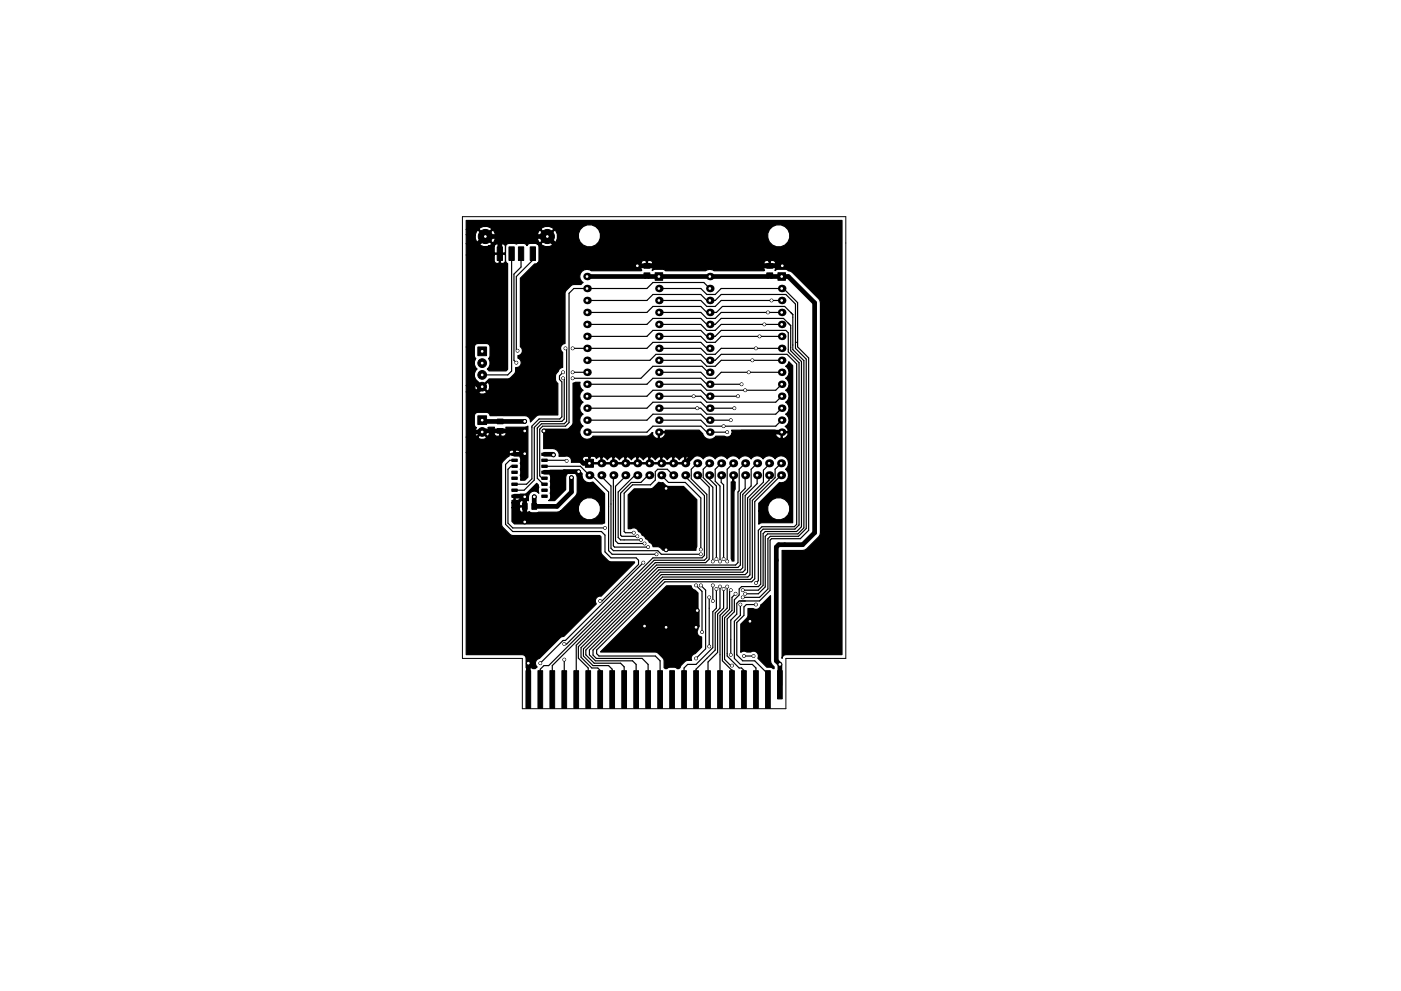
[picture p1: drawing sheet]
<svg xmlns="http://www.w3.org/2000/svg" width="297mm" height="210mm" viewBox="0 0 297 210" stroke-linecap="round" stroke-linejoin="round" font-family="sans-serif">
<path d="M98 46h81.3v93.7h-12.7v10.7h-55.9v-10.7h-12.7z" fill="none" stroke="#000" stroke-width=".21"/>
<g fill="#000" stroke="#000" stroke-width=".21">
<path d="M105.4 52.4h1.1v2.9h-1.1zM107.9 52.4h1.1v2.9h-1.1zM109.9 52.4h1.1v2.9h-1.1zM112.4 52.4h1.1v2.9h-1.1zM136.5 57.9h1.3v1h-1.3zM136.5 55.9h1.3v1h-1.3zM138.9 57.9h1.6v1.6h-1.6zM162.6 57.9h1.2v1h-1.2zM162.6 55.9h1.2v1h-1.2zM164.9 57.9h1.6v1.6h-1.6zM101.3 73.6h1.9v1.9h-1.9zM101.3 88.2h1.9v1.9h-1.9z"/>
<path d="M105.4 88.9h1.3v1h-1.3zM105.4 90.9h1.3v1h-1.3zM108.5 99.9h1.2v.6h-1.2zM108.5 98.7h1.2v.5h-1.2zM108.5 97.4h1.2v.5h-1.2zM108.5 96.1h1.2v.5h-1.2zM114.9 96.1h1.1v.5h-1.1zM114.9 98.7h1.1v.5h-1.1zM114.9 99.9h1.1v.6h-1.1zM114.9 97.4h1.1v.5h-1.1zM124.1 97.4h1.7v1.7h-1.7zM108.5 105h1.2v.5h-1.2z"/>
<path d="M108.5 103.8h1.2v.5h-1.2zM108.5 102.5h1.2v.5h-1.2zM108.5 101.2h1.2v.5h-1.2zM110.8 106.8h1v1.3h-1zM112.8 106.8h1v1.3h-1zM114.9 101.2h1.1v.5h-1.1zM114.9 102.5h1.1v.5h-1.1zM114.9 103.8h1.1v.5h-1.1zM114.9 105h1.1v.5h-1.1zM111.5 142.3h1v8h-1zM114.1 142.3h1v8h-1zM116.6 142.3h1v8h-1z"/>
<path d="M119.1 142.3h1v8h-1zM121.7 142.3h1v8h-1zM124.2 142.3h1v8h-1zM126.8 142.3h1v8h-1zM129.3 142.3h1v8h-1zM131.8 142.3h1v8h-1zM134.4 142.3h1v8h-1zM136.9 142.3h1v8h-1zM139.5 142.3h1v8h-1zM142 142.3h1v8h-1zM144.5 142.3h1v8h-1zM147.1 142.3h1v8h-1z"/>
<path d="M149.6 142.3h1v8h-1zM152.2 142.3h1v8h-1zM154.7 142.3h1v8h-1zM157.2 142.3h1v8h-1zM159.8 142.3h1v8h-1zM162.3 142.3h1v8h-1zM164.9 142.3h1v6h-1z"/>
<circle cx="102.9" cy="50.2" r="1.5"/>
<circle cx="116" cy="50.2" r="1.5"/>
<circle cx="135.1" cy="56.4" r=".4"/>
<circle cx="165.9" cy="56.4" r=".4"/>
<circle cx="102.2" cy="77" r=".92"/>
<circle cx="102.2" cy="79.5" r=".92"/>
<circle cx="109.5" cy="77" r=".3"/>
<circle cx="109.7" cy="74.4" r=".3"/>
<circle cx="119.4" cy="79" r=".3"/>
<circle cx="119.9" cy="73.9" r=".3"/>
<circle cx="121.4" cy="73.9" r=".3"/>
<circle cx="121.4" cy="79" r=".3"/>
<circle cx="158.8" cy="79" r=".3"/>
<circle cx="159.5" cy="76.4" r=".3"/>
<circle cx="160.3" cy="73.9" r=".3"/>
<circle cx="161" cy="71.4" r=".3"/>
<circle cx="162.1" cy="68.8" r=".3"/>
<circle cx="162.8" cy="66.3" r=".3"/>
<circle cx="163.6" cy="63.7" r=".3"/>
<circle cx="102.2" cy="91.6" r=".92"/>
<circle cx="102.2" cy="82" r=".92"/>
<circle cx="111.3" cy="96.3" r=".4"/>
<circle cx="111.3" cy="89.4" r=".4"/>
<circle cx="111.3" cy="91.4" r=".4"/>
<circle cx="115.3" cy="91.4" r=".4"/>
<circle cx="117.3" cy="96.5" r=".4"/>
<circle cx="119.4" cy="80.3" r=".3"/>
<circle cx="120.1" cy="97.8" r=".3"/>
<circle cx="121.4" cy="80.3" r=".3"/>
<circle cx="147.1" cy="84.1" r=".3"/>
<circle cx="147.8" cy="86.6" r=".3"/>
<circle cx="153.4" cy="90.4" r=".3"/>
<circle cx="154.2" cy="91.7" r=".3"/>
<circle cx="154.9" cy="89.1" r=".3"/>
<circle cx="155.7" cy="86.6" r=".3"/>
<circle cx="156.5" cy="84.1" r=".3"/>
<circle cx="157.2" cy="81.5" r=".3"/>
<circle cx="158" cy="82.8" r=".3"/>
<circle cx="111.3" cy="110.7" r=".4"/>
<circle cx="111.3" cy="105.4" r=".4"/>
<circle cx="113.3" cy="105.4" r=".4"/>
<circle cx="121.2" cy="101.3" r=".4"/>
<circle cx="122.7" cy="100.1" r=".4"/>
<circle cx="128.3" cy="112" r=".3"/>
<circle cx="134.4" cy="113" r=".3"/>
<circle cx="135.1" cy="113.8" r=".3"/>
<circle cx="135.9" cy="114.5" r=".3"/>
<circle cx="136.4" cy="119.4" r=".3"/>
<circle cx="136.7" cy="115.3" r=".3"/>
<circle cx="137.4" cy="116.1" r=".3"/>
<circle cx="139.2" cy="117.6" r=".3"/>
<circle cx="141.2" cy="103.6" r=".4"/>
<circle cx="141.2" cy="116.6" r=".4"/>
<circle cx="148.6" cy="116.6" r=".3"/>
<circle cx="148.6" cy="117.6" r=".3"/>
<circle cx="151.1" cy="119.1" r=".3"/>
<circle cx="151.9" cy="118.6" r=".3"/>
<circle cx="152.7" cy="119.1" r=".3"/>
<circle cx="153.4" cy="118.6" r=".3"/>
<circle cx="154.2" cy="119.1" r=".3"/>
<circle cx="119.6" cy="136.6" r=".3"/>
<circle cx="119.6" cy="139.9" r=".3"/>
<circle cx="127.3" cy="127.5" r=".3"/>
<circle cx="136.7" cy="132.8" r=".4"/>
<circle cx="141.2" cy="133.1" r=".4"/>
<circle cx="147.6" cy="133.1" r=".4"/>
<circle cx="147.6" cy="139.7" r=".3"/>
<circle cx="147.6" cy="124.2" r=".3"/>
<circle cx="147.8" cy="129.5" r=".4"/>
<circle cx="148.6" cy="124.2" r=".3"/>
<circle cx="148.8" cy="134.1" r=".3"/>
<circle cx="150.4" cy="137.2" r=".3"/>
<circle cx="150.4" cy="126.7" r=".3"/>
<circle cx="151.1" cy="127.5" r=".3"/>
<circle cx="151.1" cy="124.2" r=".3"/>
<circle cx="151.9" cy="125" r=".3"/>
<circle cx="152.7" cy="124.5" r=".3"/>
<circle cx="153.4" cy="125" r=".3"/>
<circle cx="154.2" cy="124.5" r=".3"/>
<circle cx="154.9" cy="138.9" r=".3"/>
<circle cx="154.9" cy="125.2" r=".3"/>
<circle cx="156" cy="126" r=".3"/>
<circle cx="157" cy="128.3" r=".3"/>
<circle cx="157.5" cy="126.7" r=".3"/>
<circle cx="157.5" cy="125.2" r=".3"/>
<circle cx="157.7" cy="139.2" r=".3"/>
<circle cx="158" cy="126" r=".3"/>
<circle cx="159" cy="131.8" r=".4"/>
<circle cx="159.8" cy="139.2" r=".3"/>
<circle cx="160.3" cy="128.3" r=".3"/>
<circle cx="160.3" cy="123.7" r=".3"/>
<circle cx="112" cy="140.7" r=".4"/>
<circle cx="114.6" cy="140.7" r=".3"/>
<circle cx="155.2" cy="141.2" r=".3"/>
<circle cx="165.4" cy="141" r=".4"/>
</g>
<g fill="#000">
<circle cx="124.5" cy="58.7" r=".8"/>
<circle cx="150.5" cy="58.7" r=".8"/>
<circle cx="124.5" cy="63.7" r=".8"/>
<circle cx="124.5" cy="61.2" r=".8"/>
<circle cx="124.5" cy="76.4" r=".8"/>
<circle cx="124.5" cy="66.3" r=".8"/>
<circle cx="124.5" cy="79" r=".8"/>
<circle cx="124.5" cy="71.4" r=".8"/>
<circle cx="124.5" cy="68.8" r=".8"/>
<circle cx="124.5" cy="73.9" r=".8"/>
<circle cx="139.7" cy="61.2" r=".8"/>
<circle cx="139.7" cy="63.7" r=".8"/>
<circle cx="139.7" cy="68.8" r=".8"/>
<circle cx="139.7" cy="71.4" r=".8"/>
<circle cx="139.7" cy="73.9" r=".8"/>
<circle cx="139.7" cy="76.4" r=".8"/>
<circle cx="139.7" cy="66.3" r=".8"/>
<circle cx="139.7" cy="79" r=".8"/>
<circle cx="150.5" cy="61.2" r=".8"/>
<circle cx="150.5" cy="63.7" r=".8"/>
<circle cx="150.5" cy="79" r=".8"/>
<circle cx="150.5" cy="76.4" r=".8"/>
<circle cx="150.5" cy="68.8" r=".8"/>
<circle cx="150.5" cy="73.9" r=".8"/>
<circle cx="150.5" cy="71.4" r=".8"/>
<circle cx="150.5" cy="66.3" r=".8"/>
<circle cx="165.7" cy="61.2" r=".8"/>
<circle cx="165.7" cy="66.3" r=".8"/>
<circle cx="165.7" cy="71.4" r=".8"/>
<circle cx="165.7" cy="63.7" r=".8"/>
<circle cx="165.7" cy="73.9" r=".8"/>
<circle cx="165.7" cy="76.4" r=".8"/>
<circle cx="165.7" cy="79" r=".8"/>
<circle cx="165.7" cy="68.8" r=".8"/>
<circle cx="124.5" cy="81.5" r=".8"/>
<circle cx="124.5" cy="91.7" r=".8"/>
<circle cx="124.5" cy="89.1" r=".8"/>
<circle cx="124.5" cy="86.6" r=".8"/>
<circle cx="124.5" cy="84.1" r=".8"/>
<circle cx="127.5" cy="98.3" r=".85"/>
<circle cx="130" cy="98.3" r=".85"/>
<circle cx="132.6" cy="98.3" r=".85"/>
<circle cx="135.1" cy="98.3" r=".85"/>
<circle cx="137.7" cy="98.3" r=".85"/>
<circle cx="139.7" cy="84.1" r=".8"/>
<circle cx="139.7" cy="86.6" r=".8"/>
<circle cx="139.7" cy="91.7" r=".8"/>
<circle cx="139.7" cy="89.1" r=".8"/>
<circle cx="139.7" cy="81.5" r=".8"/>
<circle cx="140.2" cy="98.3" r=".85"/>
<circle cx="142.7" cy="98.3" r=".85"/>
<circle cx="145.3" cy="98.3" r=".85"/>
<circle cx="147.8" cy="98.3" r=".85"/>
<circle cx="150.4" cy="98.3" r=".85"/>
<circle cx="150.5" cy="89.1" r=".8"/>
<circle cx="150.5" cy="84.1" r=".8"/>
<circle cx="150.5" cy="81.5" r=".8"/>
<circle cx="150.5" cy="91.7" r=".8"/>
<circle cx="150.5" cy="86.6" r=".8"/>
<circle cx="152.9" cy="98.3" r=".85"/>
<circle cx="155.4" cy="98.3" r=".85"/>
<circle cx="158" cy="98.3" r=".85"/>
<circle cx="160.5" cy="98.3" r=".85"/>
<circle cx="163.1" cy="98.3" r=".85"/>
<circle cx="165.6" cy="98.3" r=".85"/>
<circle cx="165.7" cy="81.5" r=".8"/>
<circle cx="165.7" cy="91.7" r=".8"/>
<circle cx="165.7" cy="84.1" r=".8"/>
<circle cx="165.7" cy="89.1" r=".8"/>
<circle cx="165.7" cy="86.6" r=".8"/>
<circle cx="125" cy="100.8" r=".85"/>
<circle cx="127.5" cy="100.8" r=".85"/>
<circle cx="130" cy="100.8" r=".85"/>
<circle cx="132.6" cy="100.8" r=".85"/>
<circle cx="135.1" cy="100.8" r=".85"/>
<circle cx="137.7" cy="100.8" r=".85"/>
<circle cx="140.2" cy="100.8" r=".85"/>
<circle cx="142.7" cy="100.8" r=".85"/>
<circle cx="145.3" cy="100.8" r=".85"/>
<circle cx="147.8" cy="100.8" r=".85"/>
<circle cx="150.4" cy="100.8" r=".85"/>
<circle cx="152.9" cy="100.8" r=".85"/>
<circle cx="155.4" cy="100.8" r=".85"/>
<circle cx="158" cy="100.8" r=".85"/>
<circle cx="160.5" cy="100.8" r=".85"/>
<circle cx="163.1" cy="100.8" r=".85"/>
<circle cx="165.6" cy="100.8" r=".85"/>
</g>
<g fill="none" stroke="#000" stroke-width="1">
<path d="M105.9 50.2l.1 3.6M105.9 50.2v.3M124.5 58.7h12.4l.3-.3 .2 .3h25.5l.3-.3 .3 .3h3.6l5.6 5.6v48.7l-2.5 2.6h-5.1l-.5 .5v24.1l.8 .8v4.3M135.1 56.4h.1M163.2 56.4h.1M165.9 56.4h-43.7l-6.2-6.2h-13.1l-2.8 2.8v27.5l1.5 1.5h.6l-2.4 2.5v6.4l.7 .7M165.9 56.4h-.1M100.5 91.6l-.9 1v42.8l1.7 1.8h9.2l1.5 1.5v7.6M102.2 89.1l.3 .3h8.7M111.2 91.4h-8.7l-.3 .2h-1.7M111.2 91.4h.1M111.3 89.4h-.1"/>
<path d="M111.3 96.3l-.2 .1h-2M115.3 91.4h6.4l1 1.1v4.8l1 1h1.3M115.4 96.4h1.8l.1 .1M165.7 91.7h-8.5l-4 4.1h-5.4l-2.5 2.5M109.1 105.3h2l.2 .1v5.3M111.3 107.4h.1M111.3 110.7h.1M113.3 105.4h.1M121.2 101.3v3.1l-3.1 3h-4.8v-2M122.7 100.1l-7.3 .1M141.2 103.6v13M136.7 132.8l.2 .3h4.3"/>
<path d="M147.8 129.5v3.3l-.2 .3"/>
</g>
<g fill="none" stroke="#000" stroke-width=".25">
<path d="M108.5 53.8v24.9l-.9 .8h-5.4M110.5 53.8v2.9l-1.5 1.5v18.2l.5 .6M113 53.8v1.4l-3.5 3.5v15.5l.2 .2M137.5 58.7v.2M119.4 79l-.8 .8v.7l.5 .5v7.4l-.4 .5h-4.4l-1.5 1.5v11.2l-1.2 1.1h-2.5M119.9 73.9l.2 .3v15.2l-.5 .5h-4.8l-.9 .9v10.7l1.3 1.2h.2M121.4 79h3.1M121.4 73.9h15.8l1.2-1.3h10.2l1.3 1.3h.6M124.5 71.4h12.7l1.2-1.3h10.2l1.3 1.3h1.7l1.3-1.3h13.7l.5 .5v4.1l2.3 2.3v34.4l-.9 .9h-6.7l-.5 .5v11.1l-.5 .6h-3.6l-.5 .5v1.2l-1 1v2.6l-1.5 1.5v7.9l2.5 2.5h.5l.5 .5v4.1M124.5 66.3h12.7l1.2-1.3h10.2l1.3 1.3h2l1.3-1.3h13.2l1.7 1.7v7.5l2.3 2.3v35.5l-1.2 1.3h-6.4l-.6 .5v10.7l-1.4 1.5h-2.8M124.5 68.8h12.7l1.2-1.2h10.2l1.3 1.2h1.7l1.3-1.2h13.2l1.5 1.5v5.3l2.3 2.3v35.1l-1 1h-6.7l-.4 .4v11l-1 1h-3.3M124.5 76.4h13.3l1.3-1.2h9.5l1.3 1.2h1.7l1.3-1.2h14l2 2v34l-.5 .6h-6.9l-.7 .7v10.7l-.5 .5"/>
<path d="M124.5 63.7h12.7l1.2-1.2h10.2l1.3 1.2h1.7l1.3-1.2h13.7l2.1 2v9.4l2.2 2.3v35.9l-1.6 1.7h-6l-.5 .5v10.7l-1.8 1.7h-3.5M139.7 61.2h8.9l1.3 1.3h1.7l1.3-1.3h13.2l3 3v9.4l2.3 2.3v36.6l-1.7 1.8h-6.1l-.3 .3v10.7l-2.3 2.2h-4.3l-.5 .5v2.3l-1.3 1.3v7.3M139.7 79h8.9l1.3 1.3h1.7l1.3-1.3h12.8M139.7 76.4h8.9l1.3 1.3h1.7l1.3-1.3h12.8M139.7 73.9h8.9l1.3 1.3h1.7l1.3-1.3h12.8M139.7 71.4h8.9l1.3 1.2h1.7l1.3-1.2h12.8M139.7 68.8h8.9l1.3 1.3h1.7l1.3-1.3h12.8M139.7 66.3h8.9l1.3 1.3h1.7l1.3-1.3h12.8M139.7 63.7h8.9l1.3 1.3h1.7l1.3-1.3h12.8M150.5 61.2l-1.3-1.3h-10.8l-1.2 1.3h-15.5l-1.1 1v27.5l-.7 .7h-4.8l-.7 .7v9.9l.5 .5h.5M150.5 79h-.4l-1.3-1.3h-10.4l-2.5 2.6h-14.5M168.7 72.6h.1"/>
<path d="M109.1 98.9h-.8l-.6 .7v11.4l1 1h19.6M109.1 97.7h-1l-.9 .8v12.7l1.5 1.6h18.8l.8 .7v3.6l1.2 1.3h5.4l.5 .5v.9l-7.8 7.7h-.3M115.4 98.9h7.7l1.9 1.9h.5l3.5 3.6v12.4l.8 .8h9.4M115.4 97.7h4.6l.1 .1M119.4 80.3l.2 .2v8.4l-.5 .5h-4.5l-1.3 1.3v11.1l-2.2 2.2h-2M124.5 84.1h12.7l1.2-1.3h10.2l1.3 1.3h6.6M124.5 86.6h12.7l1.2-1.3h10.2l1.3 1.3h5.8M124.5 89.1h12.7l1.2-1.2h10.2l1.3 1.2h5M124.5 91.7h12.7l1.2-1.3h10.2l1.3 1.3h4.3M124.5 81.5h12.7l1.2-1.2h10.2l1.3 1.2h7.3M139.7 84.1h8.9l1.3 1.2h14.6l1.2-1.2M139.7 86.6h8.9l1.3 1.3h14.6l1.2-1.3"/>
<path d="M139.7 89.1h8.9l1.3 1.3h14.6l1.2-1.3M139.7 81.5h8.9l1.3 1.3h14.6l1.2-1.3M147.8 98.3l-1.2 1.3v2l3.3 3.3v13.5l-.5 .5h-10.7l-22.4 22.3h-1l-.7 .8v4.3M150.4 98.3l-1.3 1.3v1.7l2 2.1v15.7M152.9 98.3l-1.3 1.3v2.5l1.1 1v16M155.4 98.3l-1.2 1.3v19.5M158 98.3l-1.3 1.3v4.5l-.2 .3v15l-.5 .5h-16.8l-17 17v9.4M160.5 98.3l-1.2 1.3v3.5l-1.8 1.8v15.5l-.5 .5h-17.3l-16.5 16.5v2l2.3 2.3h1.2l.6 .5v4.1M163.1 98.3v.2l-1.2 1.3v2.5l-3.4 3.4v15.7l-.5 .5h-17.8l-16 16v1l1.8 1.8h5.6l.7 .8v4.8M165.6 98.3l-1.3 1.3v1.7l-4.8 4.9v16.3l-.4 .4h-18.4l-15 15v1.1l.7 .7h9.7l1.3 1.3v5.3M128 100.8h-.5v.3l2 2v13.2l.5 .5h9.4l.8 .8h8.4M130 100.8v15l.3 .3h7.1"/>
<path d="M132.6 100.8v.3l-2.1 2.1v11.5l.6 .6h5.6M135.1 100.8h-.5l-3.5 3.6v9.6l.5 .5h4.3M136.4 119.4l-16.5 16.5h-.5l-4.8 4.8M137.7 100.8h-.3l-1.5 1.6h-2l-2.3 2.2v8.9l.2 .3h3.3M140.2 101.3v-.5l1.5 1.6h3.6l3.3 3.3v10.9M142.7 100.8l-1.2-1.2h-2.1l-.5 .5v1.7l-1 1.1h-3.8l-1.8 1.7v8.2l.3 .2h1.8M145.3 100.8v.3l4.1 4.1v12.7l-.6 .5h-10.4l-18.3 18.2h-.5M147.8 100.8l2.6 2.6v15.2l-.8 .8h-10.7l-21.8 21.8v5.1M150.4 100.8v.8l1.5 1.5v15.5M152.9 100.8v1.6l.5 .5v15.7M158 100.8v2.8l-1 1v15.3l-.5 .5h-17.1l-16.8 16.8v2.4l2.1 2.1v4.6M160.5 100.8v1.8l-2.5 2.6v15.7l-.5 .5h-17.5l-16.3 16.3v1.5l2 2h3.3l.8 .8v4.3"/>
<path d="M163.1 100.8v1l-4.1 4.1v16.1l-.4 .4h-18.1l-15.5 15.5v1l1.2 1.3h7.9l.8 .8v5.3M165.6 100.8l-5.6 5.6v16.4l-.6 .6h-18.4l-14.5 14.5v.8l.5 .5h11.9l1.1 1v6.1M119.6 139.9v6.4M147.6 124.2l1.2 1.3v8.6M148.6 124.2l1 1v12.5l-2 2M150.4 126.7v10.5M151.1 124.2v3.3M151.9 125v4l-.8 .8v7.6l-3.5 3.6h-1.8l-.8 .7v4.6M152.7 124.5v4.5l-1.1 1v7.9l-4 4.1v4.3M153.4 125v4l-1.3 1.3v8.1l-2 2.1v5.8M154.2 124.5v4.5l-1.5 1.6v15.7M154.9 125.2l-.2 .3v3.8l-1.5 1.5v9.4l1.9 2"/>
<path d="M156 126l-.8 .7v2.8l-1.6 1.6v8.8l1.3 1.3h.3M157 128.3v2.3l-1.3 1.2v7.9l1.3 1.3h2.5l.8 .7v4.6M157.7 139.2h2.1M160.3 128.3h-2.1l-.5 .5v1.8l-1.5 1.5v6.8l1.3 1.3h2.5l2.8 2.8v3.3M155.1 142.2h.1M155.1 142.2l.1 4.1"/>
</g>
<path d="M121.5 81.3l.5-.2h1a1.41 1.41 0 0 0 .6 1.7 1.47 1.47 0 0 0 0 2.5 1.47 1.47 0 0 0 0 2.6 1.47 1.47 0 0 0 0 2.5 1.52 1.52 0 0 0-.2 2.4 1.52 1.52 0 0 0 2.3-.3h11.5l1.2-.7a1.02 1.02 0 0 0 1 1.3l.2-.1v-1.2h.2v1.2a.95 .95 0 0 0 1.2-1.2h-1.4v-.2h1.4l.1-.3h7.1l.8 .7 .1 .3a1.55 1.55 0 0 0 2.7 .2l1.8 .1a1.02 1.02 0 0 0 1.5-.6h9.2l.6 .8 .5 .3 .2-.1v-1.2h.3v1.2a.95 .95 0 0 0 1.1-1.2h-2.5l-.2 .2h-9.2v-.7h9.3l.1 .3h2.5l.1-.3-.1-.3-.5-.5a1.48 1.48 0 0 0 .1-2.6 1.47 1.47 0 0 0 0-2.6 1.47 1.47 0 0 0 0-2.5 1.47 1.47 0 0 0 0-2.5 1.47 1.47 0 0 0 0-2.6l.2-.2 .4-.8 .9 .9v33.3h-6.6l-.6 .3v-2.8h1.9a2.37 2.37 0 0 0 3.6 1.5 2.37 2.37 0 0 0 0-3.9 2.37 2.37 0 0 0-3.6 1.5v.9h-1.9v-1.6l4.4-4.4a1.57 1.57 0 0 0 1.8-.9 1.57 1.57 0 0 0-.6-1.9 1.57 1.57 0 0 0 .2-2.4 1.57 1.57 0 0 0-2.4 .2 1.51 1.51 0 0 0-2.5 0 1.51 1.51 0 0 0-2.5 0 1.51 1.51 0 0 0-2.6 0 1.51 1.51 0 0 0-2.5 0 1.51 1.51 0 0 0-2.6 0 1.51 1.51 0 0 0-2.5 0 1.51 1.51 0 0 0-2.6 .1l-.4-.5-.5-.1-.2 .1v1.4h-20.6v-1.4h.3v1.2h2.3v-1.2h.2v1.2h2.3v-1.2h.3v1.2h2.3v-1.2h.2v1.2h2.3v-1.2h.3v1.2h2.2v-1.2h.3v1.2h2.3v-1.2h.2v1.2h2.3v-1.2h.3v1.2h2.3v-1.2l-.3-.1-.4 .1-.5 .6-.5-.6-.4-.1-.2 .1-.5-.1-.4 .1-.5 .6-.5-.6-.4-.1-.3 .1-.4-.1-.5 .1-.5 .6-.5-.6-.4-.1-.2 .1-.5-.1-.4 .1-.5 .6-.5-.6-.4-.1-.2 .1-.5-.1-.4 .1-.5 .6-.5-.6-.5-.1-.2 .1-.5-.1-.4 .1-.5 .6-.5-.6-.4-.1-.2 .1-.5-.1-.4 .1-.5 .6-.5-.6-.4-.1-.3 .1-.4-.1-.8 .4-.5-.5h-.6l-.2 .2-1.1-.2-.5 .5v.7l.1 .2-2.4-.2a1.03 1.03 0 0 0-1.4-1.2h-1.3v-.8l-.8-.7-2.4-.1v-3.8l.1-.1 4.8-.1a2.37 2.37 0 0 0 1.3-1.5zM108.9 105.2h1.2l.2-.3 1.2-.1 2.3-2.3 .3 .4 .2 .5-.2 .4 .1 .9a1.22 1.22 0 0 0-1.3-.4 1.22 1.22 0 0 0-.9 1.1v.8h-.4l-.2 .1v2.2a.55 .55 0 0 0 .8 0v.1a2.12 2.12 0 0 0 1.8 .2l4.1-.1 .7-.3h3.8a2.37 2.37 0 0 0 3.7 1.5 2.37 2.37 0 0 0 0-3.9 2.37 2.37 0 0 0-3.7 1.5v.9h-3.8l3.5-3.5 .1-3.6a1.23 1.23 0 0 0-1.2-1.2 1.23 1.23 0 0 0-1.3 1.2v2.6l-2.3 2.3h-1.3a1.41 1.41 0 0 0 .4-1.7l.1-2-.2-.4a2.32 2.32 0 0 0-.1-1.8h-1.2v-.2h1.2l.1-.3h6.1l.7 .7a1.54 1.54 0 0 0 .6 1.6 1.54 1.54 0 0 0 1.7 .1l2.5 2.5v6.3l-.5 .2h-18.6l-.6-.6v-2.9h1.6v.5a.61 .61 0 0 0 1 .3v-.9l-2.6 .1v-1h1.6v.5l.2 .1h.8v-1a.6 .6 0 0 0-1 .4h-1.6v-.5l.5-.2v-.6h.2v.6l.2 .2a.71 .71 0 0 0 .9-.5l-.2-.3h-1.2zM133.2 105l1.3-1.3h3.7l1.4-1.4 .9 .1 .6 .6 .6 .2h3.2l2.8 2.8v10l-.1 .7h-7a1.8 1.8 0 0 0-2.2-.7 .98 .98 0 0 0-.7-.9l-.5-.7-.3-.1-.4-.6-1.1-.9a1.03 1.03 0 0 0-1.6-.6h-.6zM155.3 100.7h.3v1.5h.3v1.6l-.3 .6v14.6h-.4l-.2-.5v-16.3h.3zM141.3 124.3h5.2a.99 .99 0 0 0 .9 .9l.6 .6v7.7a1.03 1.03 0 0 0 .8 1.6v2.2l-1.4 1.4a1.02 1.02 0 0 0-.8 1.4 2.13 2.13 0 0 0-2.4 1.6l-.2 .2-.5-.1a2 2 0 0 0-2 0l-.5 .1-.2-.2a2.69 2.69 0 0 0-1.9-3.4h-11.6zM98.8 46.8h79.7v92.1h-11.9l-.5 .2-.3 .6v-22.9l4.8-.1 3-2.8 .3-.9v-48.7l-.3-.9-5.6-5.6-1.5-.7h-1.6l-.6 .2a.55 .55 0 0 0 0-.8h-2.2l-.2 .2 .2 .6-.1 .1h-10.6a1.47 1.47 0 0 0-1.8 0h-8.5l-.6-.3h-1.6l-.7 .2a.55 .55 0 0 0 .1-.8h-2.2l-.2 .2 .2 .6-.1 .1h-10.7a1.52 1.52 0 0 0-2.1 .4 1.52 1.52 0 0 0 .4 2.1l-.4 .5h-1.9a2.85 2.85 0 0 0-1.5 1.8v10.7h-.1a1.04 1.04 0 0 0-.8 .8 1.04 1.04 0 0 0 .4 1.1v3.2h-.1a1.03 1.03 0 0 0-.8 .8 1.69 1.69 0 0 0-.1 2.6v6.6l-4.3 .1-1.5 1.4v-.1a1.21 1.21 0 0 0-1.3-1.2h-7.3l-.2-.5-.3-.2h-2.1a.74 .74 0 0 0-.7 .7v1.9l.2 .5 .2 .2h-.1a1.18 1.18 0 0 0 .2 1.8l1.1-1.1 1.1 1.1 .3-.1 .2-.8h1a.68 .68 0 0 0 .5 .9h.5l.1-.2v-.9h.3v.9l.1 .2 .7-.1a.59 .59 0 0 0 .1-1l-3.3 .2v-.4l-.4-.5 1.4-.2v.5l.1 .2h2.2l.2-.2-.1-.5h4l.7-.2v10.8l-.6 .7h-.9l-.1-1.1 .1-.9-.1-.3 .1-.9-.1-.4a2.32 2.32 0 0 0-.2-1.8h-2.1l-.1 .3a2.85 2.85 0 0 0-1.5 1.4l-.1 13 .3 .6 1.5 1.6 .6 .2h18.5l.2 .3 .1 3.5 1.4 1.6 .6 .2h5v.2l-7 7.1h-.4a1.03 1.03 0 0 0-.7 1.6l-6.9 6.9-.7 .3-4.4 4.4a1.03 1.03 0 0 0-.9 .7 1.03 1.03 0 0 0 .4 1.1l-.4 .4h-.5l-.4-.2-.7 .2-.4-.2v-2.3l-.2-.3-.6-.2h-11.9v-42.9h9.1l.1 .3h1v-.6h.2v.6h.9l.2-.2-.1-.3-.4-.3h-.4l-.2 .2-.4-.2a.71 .71 0 0 0-.9 .5h-9.1v-3.3h2.5l.1 .3a1.18 1.18 0 0 0 1.8-.3l-1-.9-.9 .9h-2.5v-9.6h2.5l.1 .3a1.18 1.18 0 0 0 1.8-.3l-1-.9-.9 .9h-2.5v-1.3h1.9v.6l.2 .5 .2 .1 1-1h.3l.9 1 .3-.1a1.18 1.18 0 0 0-.3-1.8l-.9 .9h-.3l-1-.9-.2 .1-.2 .6h-1.9v-8.2h1.8v1.9l.3 .6a1.61 1.61 0 0 0 .2 2.2 1.64 1.64 0 0 0 .2 2.7l.9 .9 1.5-1.5h3.9a2.18 2.18 0 0 0 1.7-2.4 1.03 1.03 0 0 0 1.2-.8 1.03 1.03 0 0 0-.7-1.2v-.6h.1a1.04 1.04 0 0 0 .9-.8 1.04 1.04 0 0 0-.5-1v-14.6l3-3 .8-.2h21.8l.2 .5h.9v-.9h.3v.9h1l.1-.5h23.5l.2 .5h1v-.9h.2v.9h1a.6 .6 0 0 0-.4-1h-.4l-.2 .1-.9-.1-.5 .5h-23.5l-.5-.5h-.5l-.1 .1-.9-.1-.5 .5h-21.8l.2-.5v-2.9l-.2-.5-.3-.2h.9l.2 .3a1.78 1.78 0 0 0 2.5-.3l-1.4-1.3-1.3 1.3-2.3-.1-.5 .2-.2 .3-.4-.4a2.42 2.42 0 0 0-1.8 .1 2.42 2.42 0 0 0-1.9-.1l-.2 .1-.2 .6v2.9l.2 .5 .2 .1v22.5l-.3 .3h-3.6l-.4-.4a1.61 1.61 0 0 0 .3-2.2l.3-.6v-1.9a.74 .74 0 0 0-.7-.7h-1.9l-.5 .2-.2 .5h-1.8v-19.5h6l.1 1.5 .4 .3h.4l.1-.2v-1.8h.3v1.8l.2 .2a.71 .71 0 0 0 .9-.5v-1.3l-.2-.2h-2.1l-.1 .2h-6v-2.4h2.8l.1 .3 .8 .3h2.3v1.2l.1 .2h.9v-1.8h.3v1.8h.9l.2-.2-.1-1.5-.4-.3h-.4l-.2 .2-.4-.2a.71 .71 0 0 0-.9 .6h-1.3l.6-.3 .1-.3-1.3-1.3-1.3 1.3h-2.8v-1.9h2v.8l.3 .8 .3 .1 1.3-1.3h.4l1.3 1.3 .3-.1 .3-.8v-.8h8.9v.8l.3 .8 .3 .1 1.4-1.3h.3l1.4 1.3 .3-.1 .3-.9h4.4a2.37 2.37 0 0 0 2.4 1.9 2.37 2.37 0 0 0 2.3-1.9h35.5l.3 .8a2.37 2.37 0 0 0 4 .1 2.37 2.37 0 0 0-1.5-3.7 2.37 2.37 0 0 0-2.8 2.8h-35.5v-.9a2.37 2.37 0 0 0-2.8-1.9 2.37 2.37 0 0 0-1.9 2.8h-4.4v-.8l-.3-.7-.3-.2-1.4 1.4h-.3l-1.4-1.4-.3 .2-.3 .8h-8.9l-.3-.8-.3-.2-1.3 1.4h-.4l-1.3-1.4-.3 .2-.3 .8h-2v-1.1h2.8l1.3 1.3 1.3-1.3h10.5l1.3 1.3 1.4-1.3a1.66 1.66 0 0 0-2.7 0h-10.5l-.1-.4a1.78 1.78 0 0 0-2.5 .4h-2.8zM158.6 129.1h1.1a1.09 1.09 0 0 0 1.7-.8l2-1.9v13.8l.1 .5 .6 .8v.4l-.8-.3h-.7l-1.9-1.9a1.03 1.03 0 0 0-.2-1.3 1.03 1.03 0 0 0-1.3-.1h-.9a1 1 0 0 0-1.2 .1v-6l1.4-1.5z" fill="#000" stroke="#000" stroke-width=".25"/>
<g fill="#fff" stroke="#fff" stroke-width=".21">
<circle cx="111.3" cy="89.4" r=".17"/>
<circle cx="165.4" cy="141" r=".17"/>
<circle cx="113.3" cy="105.4" r=".17"/>
<circle cx="117.3" cy="96.5" r=".17"/>
<circle cx="121.2" cy="101.3" r=".17"/>
<circle cx="159" cy="131.8" r=".17"/>
<circle cx="165.9" cy="56.4" r=".17"/>
<circle cx="141.2" cy="103.6" r=".17"/>
<circle cx="141.2" cy="116.6" r=".17"/>
<circle cx="136.7" cy="132.8" r=".17"/>
<circle cx="141.2" cy="133.1" r=".17"/>
<circle cx="147.6" cy="133.1" r=".17"/>
<circle cx="147.8" cy="129.5" r=".17"/>
<circle cx="111.3" cy="110.7" r=".17"/>
<circle cx="135.1" cy="56.4" r=".17"/>
<circle cx="122.7" cy="100.1" r=".17"/>
<circle cx="112" cy="140.7" r=".17"/>
<circle cx="111.3" cy="96.3" r=".17"/>
<circle cx="115.3" cy="91.4" r=".17"/>
<circle cx="111.3" cy="91.4" r=".17"/>
<circle cx="111.3" cy="105.4" r=".17"/>
<circle cx="109.5" cy="77" r=".17"/>
<circle cx="109.7" cy="74.4" r=".17"/>
<circle cx="139.2" cy="117.6" r=".17"/>
<circle cx="147.1" cy="84.1" r=".17"/>
<circle cx="119.6" cy="136.6" r=".17"/>
<circle cx="119.6" cy="139.9" r=".17"/>
<circle cx="147.8" cy="86.6" r=".17"/>
<circle cx="153.4" cy="90.4" r=".17"/>
<circle cx="157" cy="128.3" r=".17"/>
<circle cx="154.2" cy="91.7" r=".17"/>
<circle cx="151.1" cy="127.5" r=".17"/>
<circle cx="151.1" cy="124.2" r=".17"/>
<circle cx="151.1" cy="119.1" r=".17"/>
<circle cx="154.9" cy="89.1" r=".17"/>
<circle cx="151.9" cy="118.6" r=".17"/>
<circle cx="151.9" cy="125" r=".17"/>
<circle cx="155.7" cy="86.6" r=".17"/>
<circle cx="152.7" cy="124.5" r=".17"/>
<circle cx="152.7" cy="119.1" r=".17"/>
<circle cx="156.5" cy="84.1" r=".17"/>
<circle cx="153.4" cy="125" r=".17"/>
<circle cx="153.4" cy="118.6" r=".17"/>
<circle cx="157.2" cy="81.5" r=".17"/>
<circle cx="154.2" cy="124.5" r=".17"/>
<circle cx="154.2" cy="119.1" r=".17"/>
<circle cx="158" cy="82.8" r=".17"/>
<circle cx="158.7" cy="79" r=".17"/>
<circle cx="159.5" cy="76.4" r=".17"/>
<circle cx="160.3" cy="73.9" r=".17"/>
<circle cx="161" cy="71.4" r=".17"/>
<circle cx="162.1" cy="68.8" r=".17"/>
<circle cx="162.8" cy="66.3" r=".17"/>
<circle cx="163.6" cy="63.7" r=".17"/>
<circle cx="119.9" cy="73.9" r=".17"/>
<circle cx="121.4" cy="73.9" r=".17"/>
<circle cx="119.4" cy="80.3" r=".17"/>
<circle cx="121.4" cy="80.3" r=".17"/>
<circle cx="119.4" cy="79" r=".17"/>
<circle cx="121.4" cy="79" r=".17"/>
<circle cx="154.9" cy="138.9" r=".17"/>
<circle cx="160.3" cy="128.3" r=".17"/>
<circle cx="160.3" cy="123.7" r=".17"/>
<circle cx="157.5" cy="125.2" r=".17"/>
<circle cx="154.9" cy="125.2" r=".17"/>
<circle cx="158" cy="126" r=".17"/>
<circle cx="156" cy="126" r=".17"/>
<circle cx="155.2" cy="141.2" r=".17"/>
<circle cx="157.5" cy="126.7" r=".17"/>
<circle cx="150.4" cy="126.7" r=".17"/>
<circle cx="150.4" cy="137.2" r=".17"/>
<circle cx="148.6" cy="124.2" r=".17"/>
<circle cx="147.6" cy="139.7" r=".17"/>
<circle cx="148.6" cy="117.6" r=".17"/>
<circle cx="137.4" cy="116.1" r=".17"/>
<circle cx="136.7" cy="115.3" r=".17"/>
<circle cx="135.9" cy="114.5" r=".17"/>
<circle cx="135.1" cy="113.8" r=".17"/>
<circle cx="147.6" cy="124.2" r=".17"/>
<circle cx="148.6" cy="116.6" r=".17"/>
<circle cx="148.8" cy="134.1" r=".17"/>
<circle cx="134.4" cy="113" r=".17"/>
<circle cx="136.4" cy="119.4" r=".17"/>
<circle cx="114.6" cy="140.7" r=".17"/>
<circle cx="120.1" cy="97.8" r=".17"/>
<circle cx="159.8" cy="139.2" r=".17"/>
<circle cx="128.3" cy="112" r=".17"/>
<circle cx="157.7" cy="139.2" r=".17"/>
<circle cx="127.3" cy="127.5" r=".17"/>
<circle cx="102.9" cy="50.2" r=".17"/>
<circle cx="116" cy="50.2" r=".17"/>
<circle cx="102.2" cy="89.1" r=".17"/>
<circle cx="102.2" cy="91.6" r=".17"/>
<circle cx="125" cy="98.3" r=".17"/>
<circle cx="125" cy="100.8" r=".17"/>
<circle cx="127.5" cy="98.3" r=".17"/>
<circle cx="127.5" cy="100.8" r=".17"/>
<circle cx="130" cy="98.3" r=".17"/>
<circle cx="130" cy="100.8" r=".17"/>
<circle cx="132.6" cy="98.3" r=".17"/>
<circle cx="132.6" cy="100.8" r=".17"/>
<circle cx="135.1" cy="98.3" r=".17"/>
<circle cx="135.1" cy="100.8" r=".17"/>
<circle cx="137.7" cy="98.3" r=".17"/>
<circle cx="137.7" cy="100.8" r=".17"/>
<circle cx="140.2" cy="98.3" r=".17"/>
<circle cx="140.2" cy="100.8" r=".17"/>
<circle cx="142.7" cy="98.3" r=".17"/>
<circle cx="142.7" cy="100.8" r=".17"/>
<circle cx="145.3" cy="98.3" r=".17"/>
<circle cx="145.3" cy="100.8" r=".17"/>
<circle cx="147.8" cy="98.3" r=".17"/>
<circle cx="147.8" cy="100.8" r=".17"/>
<circle cx="150.4" cy="98.3" r=".17"/>
<circle cx="150.4" cy="100.8" r=".17"/>
<circle cx="152.9" cy="98.3" r=".17"/>
<circle cx="152.9" cy="100.8" r=".17"/>
<circle cx="155.4" cy="98.3" r=".17"/>
<circle cx="155.4" cy="100.8" r=".17"/>
<circle cx="158" cy="98.3" r=".17"/>
<circle cx="158" cy="100.8" r=".17"/>
<circle cx="160.5" cy="98.3" r=".17"/>
<circle cx="160.5" cy="100.8" r=".17"/>
<circle cx="163.1" cy="98.3" r=".17"/>
<circle cx="163.1" cy="100.8" r=".17"/>
<circle cx="165.6" cy="98.3" r=".17"/>
<circle cx="165.6" cy="100.8" r=".17"/>
<circle cx="102.2" cy="74.5" r=".17"/>
<circle cx="102.2" cy="77" r=".17"/>
<circle cx="102.2" cy="79.5" r=".17"/>
<circle cx="102.2" cy="82" r=".17"/>
<circle cx="125" cy="107.9" r=".17"/>
<circle cx="165.1" cy="107.9" r=".17"/>
<circle cx="125" cy="50" r=".17"/>
<circle cx="165.1" cy="50" r=".17"/>
<circle cx="139.7" cy="58.7" r=".17"/>
<circle cx="124.5" cy="91.7" r=".17"/>
<circle cx="139.7" cy="61.2" r=".17"/>
<circle cx="124.5" cy="89.1" r=".17"/>
<circle cx="139.7" cy="63.7" r=".17"/>
<circle cx="124.5" cy="86.6" r=".17"/>
<circle cx="139.7" cy="66.3" r=".17"/>
<circle cx="124.5" cy="84.1" r=".17"/>
<circle cx="139.7" cy="68.8" r=".17"/>
<circle cx="124.5" cy="81.5" r=".17"/>
<circle cx="139.7" cy="71.4" r=".17"/>
<circle cx="124.5" cy="79" r=".17"/>
<circle cx="139.7" cy="73.9" r=".17"/>
<circle cx="124.5" cy="76.4" r=".17"/>
<circle cx="139.7" cy="76.4" r=".17"/>
<circle cx="124.5" cy="73.9" r=".17"/>
<circle cx="139.7" cy="79" r=".17"/>
<circle cx="124.5" cy="71.4" r=".17"/>
<circle cx="139.7" cy="81.5" r=".17"/>
<circle cx="124.5" cy="68.8" r=".17"/>
<circle cx="139.7" cy="84.1" r=".17"/>
<circle cx="124.5" cy="66.3" r=".17"/>
<circle cx="139.7" cy="86.6" r=".17"/>
<circle cx="124.5" cy="63.7" r=".17"/>
<circle cx="139.7" cy="89.1" r=".17"/>
<circle cx="124.5" cy="61.2" r=".17"/>
<circle cx="139.7" cy="91.7" r=".17"/>
<circle cx="124.5" cy="58.7" r=".17"/>
<circle cx="165.7" cy="58.7" r=".17"/>
<circle cx="150.5" cy="91.7" r=".17"/>
<circle cx="165.7" cy="61.2" r=".17"/>
<circle cx="150.5" cy="89.1" r=".17"/>
<circle cx="165.7" cy="63.7" r=".17"/>
<circle cx="150.5" cy="86.6" r=".17"/>
<circle cx="165.7" cy="66.3" r=".17"/>
<circle cx="150.5" cy="84.1" r=".17"/>
<circle cx="165.7" cy="68.8" r=".17"/>
<circle cx="150.5" cy="81.5" r=".17"/>
<circle cx="165.7" cy="71.4" r=".17"/>
<circle cx="150.5" cy="79" r=".17"/>
<circle cx="165.7" cy="73.9" r=".17"/>
<circle cx="150.5" cy="76.4" r=".17"/>
<circle cx="165.7" cy="76.4" r=".17"/>
<circle cx="150.5" cy="73.9" r=".17"/>
<circle cx="165.7" cy="79" r=".17"/>
<circle cx="150.5" cy="71.4" r=".17"/>
<circle cx="165.7" cy="81.5" r=".17"/>
<circle cx="150.5" cy="68.8" r=".17"/>
<circle cx="165.7" cy="84.1" r=".17"/>
<circle cx="150.5" cy="66.3" r=".17"/>
<circle cx="165.7" cy="86.6" r=".17"/>
<circle cx="150.5" cy="63.7" r=".17"/>
<circle cx="165.7" cy="89.1" r=".17"/>
<circle cx="150.5" cy="61.2" r=".17"/>
<circle cx="165.7" cy="91.7" r=".17"/>
<circle cx="150.5" cy="58.7" r=".17"/>
</g>
</svg>
